VERSION 5.7 ;
  NAMESCASESENSITIVE ON ;
  NOWIREEXTENSIONATPIN ON ;
  DIVIDERCHAR "/" ;
  BUSBITCHARS "[]" ;
UNITS
  DATABASE MICRONS 200 ;
END UNITS

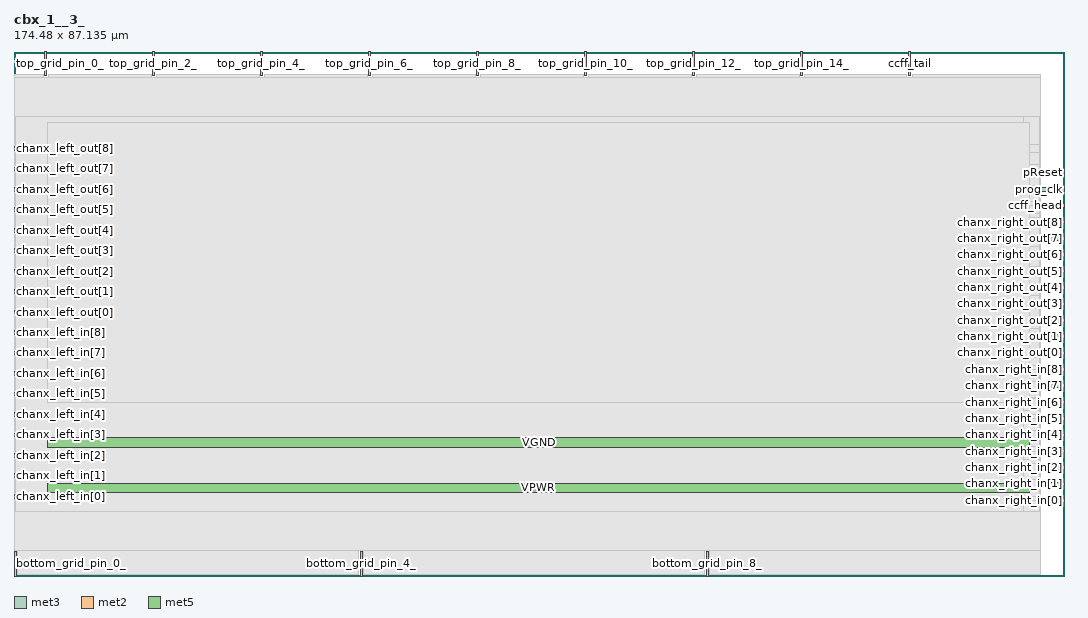
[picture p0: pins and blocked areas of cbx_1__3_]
MACRO cbx_1__3_
  CLASS BLOCK ;
  FOREIGN cbx_1__3_ ;
  ORIGIN 0.000 0.000 ;
  SIZE 174.480 BY 87.135 ;
  PIN chanx_left_in[0]
    DIRECTION INPUT ;
    PORT
      LAYER met3 ;
        RECT 0.000 12.960 4.000 13.560 ;
    END
  END chanx_left_in[0]
  PIN chanx_left_in[1]
    DIRECTION INPUT ;
    PORT
      LAYER met3 ;
        RECT 0.000 16.360 4.000 16.960 ;
    END
  END chanx_left_in[1]
  PIN chanx_left_in[2]
    DIRECTION INPUT ;
    PORT
      LAYER met3 ;
        RECT 0.000 19.760 4.000 20.360 ;
    END
  END chanx_left_in[2]
  PIN chanx_left_in[3]
    DIRECTION INPUT ;
    PORT
      LAYER met3 ;
        RECT 0.000 23.160 4.000 23.760 ;
    END
  END chanx_left_in[3]
  PIN chanx_left_in[4]
    DIRECTION INPUT ;
    PORT
      LAYER met3 ;
        RECT 0.000 26.560 4.000 27.160 ;
    END
  END chanx_left_in[4]
  PIN chanx_left_in[5]
    DIRECTION INPUT ;
    PORT
      LAYER met3 ;
        RECT 0.000 29.960 4.000 30.560 ;
    END
  END chanx_left_in[5]
  PIN chanx_left_in[6]
    DIRECTION INPUT ;
    PORT
      LAYER met3 ;
        RECT 0.000 33.360 4.000 33.960 ;
    END
  END chanx_left_in[6]
  PIN chanx_left_in[7]
    DIRECTION INPUT ;
    PORT
      LAYER met3 ;
        RECT 0.000 36.760 4.000 37.360 ;
    END
  END chanx_left_in[7]
  PIN chanx_left_in[8]
    DIRECTION INPUT ;
    PORT
      LAYER met3 ;
        RECT 0.000 40.160 4.000 40.760 ;
    END
  END chanx_left_in[8]
  PIN chanx_left_out[0]
    DIRECTION OUTPUT TRISTATE ;
    PORT
      LAYER met3 ;
        RECT 0.000 43.560 4.000 44.160 ;
    END
  END chanx_left_out[0]
  PIN chanx_left_out[1]
    DIRECTION OUTPUT TRISTATE ;
    PORT
      LAYER met3 ;
        RECT 0.000 46.960 4.000 47.560 ;
    END
  END chanx_left_out[1]
  PIN chanx_left_out[2]
    DIRECTION OUTPUT TRISTATE ;
    PORT
      LAYER met3 ;
        RECT 0.000 50.360 4.000 50.960 ;
    END
  END chanx_left_out[2]
  PIN chanx_left_out[3]
    DIRECTION OUTPUT TRISTATE ;
    PORT
      LAYER met3 ;
        RECT 0.000 53.760 4.000 54.360 ;
    END
  END chanx_left_out[3]
  PIN chanx_left_out[4]
    DIRECTION OUTPUT TRISTATE ;
    PORT
      LAYER met3 ;
        RECT 0.000 57.160 4.000 57.760 ;
    END
  END chanx_left_out[4]
  PIN chanx_left_out[5]
    DIRECTION OUTPUT TRISTATE ;
    PORT
      LAYER met3 ;
        RECT 0.000 60.560 4.000 61.160 ;
    END
  END chanx_left_out[5]
  PIN chanx_left_out[6]
    DIRECTION OUTPUT TRISTATE ;
    PORT
      LAYER met3 ;
        RECT 0.000 63.960 4.000 64.560 ;
    END
  END chanx_left_out[6]
  PIN chanx_left_out[7]
    DIRECTION OUTPUT TRISTATE ;
    PORT
      LAYER met3 ;
        RECT 0.000 67.360 4.000 67.960 ;
    END
  END chanx_left_out[7]
  PIN chanx_left_out[8]
    DIRECTION OUTPUT TRISTATE ;
    PORT
      LAYER met3 ;
        RECT 0.000 70.760 4.000 71.360 ;
    END
  END chanx_left_out[8]
  PIN top_grid_pin_0_
    DIRECTION OUTPUT TRISTATE ;
    PORT
      LAYER met2 ;
        RECT 5.150 83.135 5.430 87.135 ;
    END
  END top_grid_pin_0_
  PIN top_grid_pin_2_
    DIRECTION OUTPUT TRISTATE ;
    PORT
      LAYER met2 ;
        RECT 23.090 83.135 23.370 87.135 ;
    END
  END top_grid_pin_2_
  PIN top_grid_pin_4_
    DIRECTION OUTPUT TRISTATE ;
    PORT
      LAYER met2 ;
        RECT 41.030 83.135 41.310 87.135 ;
    END
  END top_grid_pin_4_
  PIN top_grid_pin_6_
    DIRECTION OUTPUT TRISTATE ;
    PORT
      LAYER met2 ;
        RECT 58.970 83.135 59.250 87.135 ;
    END
  END top_grid_pin_6_
  PIN top_grid_pin_8_
    DIRECTION OUTPUT TRISTATE ;
    PORT
      LAYER met2 ;
        RECT 76.910 83.135 77.190 87.135 ;
    END
  END top_grid_pin_8_
  PIN top_grid_pin_10_
    DIRECTION OUTPUT TRISTATE ;
    PORT
      LAYER met2 ;
        RECT 94.850 83.135 95.130 87.135 ;
    END
  END top_grid_pin_10_
  PIN top_grid_pin_12_
    DIRECTION OUTPUT TRISTATE ;
    PORT
      LAYER met2 ;
        RECT 112.790 83.135 113.070 87.135 ;
    END
  END top_grid_pin_12_
  PIN top_grid_pin_14_
    DIRECTION OUTPUT TRISTATE ;
    PORT
      LAYER met2 ;
        RECT 130.730 83.135 131.010 87.135 ;
    END
  END top_grid_pin_14_
  PIN ccff_tail
    DIRECTION OUTPUT TRISTATE ;
    PORT
      LAYER met2 ;
        RECT 148.670 83.135 148.950 87.135 ;
    END
  END ccff_tail
  PIN chanx_right_in[0]
    DIRECTION INPUT ;
    PORT
      LAYER met3 ;
        RECT 170.480 12.280 174.480 12.880 ;
    END
  END chanx_right_in[0]
  PIN chanx_right_in[1]
    DIRECTION INPUT ;
    PORT
      LAYER met3 ;
        RECT 170.480 15.000 174.480 15.600 ;
    END
  END chanx_right_in[1]
  PIN chanx_right_in[2]
    DIRECTION INPUT ;
    PORT
      LAYER met3 ;
        RECT 170.480 17.720 174.480 18.320 ;
    END
  END chanx_right_in[2]
  PIN chanx_right_in[3]
    DIRECTION INPUT ;
    PORT
      LAYER met3 ;
        RECT 170.480 20.440 174.480 21.040 ;
    END
  END chanx_right_in[3]
  PIN chanx_right_in[4]
    DIRECTION INPUT ;
    PORT
      LAYER met3 ;
        RECT 170.480 23.160 174.480 23.760 ;
    END
  END chanx_right_in[4]
  PIN chanx_right_in[5]
    DIRECTION INPUT ;
    PORT
      LAYER met3 ;
        RECT 170.480 25.880 174.480 26.480 ;
    END
  END chanx_right_in[5]
  PIN chanx_right_in[6]
    DIRECTION INPUT ;
    PORT
      LAYER met3 ;
        RECT 170.480 28.600 174.480 29.200 ;
    END
  END chanx_right_in[6]
  PIN chanx_right_in[7]
    DIRECTION INPUT ;
    PORT
      LAYER met3 ;
        RECT 170.480 31.320 174.480 31.920 ;
    END
  END chanx_right_in[7]
  PIN chanx_right_in[8]
    DIRECTION INPUT ;
    PORT
      LAYER met3 ;
        RECT 170.480 34.040 174.480 34.640 ;
    END
  END chanx_right_in[8]
  PIN chanx_right_out[0]
    DIRECTION OUTPUT TRISTATE ;
    PORT
      LAYER met3 ;
        RECT 170.480 36.760 174.480 37.360 ;
    END
  END chanx_right_out[0]
  PIN chanx_right_out[1]
    DIRECTION OUTPUT TRISTATE ;
    PORT
      LAYER met3 ;
        RECT 170.480 39.480 174.480 40.080 ;
    END
  END chanx_right_out[1]
  PIN chanx_right_out[2]
    DIRECTION OUTPUT TRISTATE ;
    PORT
      LAYER met3 ;
        RECT 170.480 42.200 174.480 42.800 ;
    END
  END chanx_right_out[2]
  PIN chanx_right_out[3]
    DIRECTION OUTPUT TRISTATE ;
    PORT
      LAYER met3 ;
        RECT 170.480 44.920 174.480 45.520 ;
    END
  END chanx_right_out[3]
  PIN chanx_right_out[4]
    DIRECTION OUTPUT TRISTATE ;
    PORT
      LAYER met3 ;
        RECT 170.480 47.640 174.480 48.240 ;
    END
  END chanx_right_out[4]
  PIN chanx_right_out[5]
    DIRECTION OUTPUT TRISTATE ;
    PORT
      LAYER met3 ;
        RECT 170.480 50.360 174.480 50.960 ;
    END
  END chanx_right_out[5]
  PIN chanx_right_out[6]
    DIRECTION OUTPUT TRISTATE ;
    PORT
      LAYER met3 ;
        RECT 170.480 53.080 174.480 53.680 ;
    END
  END chanx_right_out[6]
  PIN chanx_right_out[7]
    DIRECTION OUTPUT TRISTATE ;
    PORT
      LAYER met3 ;
        RECT 170.480 55.800 174.480 56.400 ;
    END
  END chanx_right_out[7]
  PIN chanx_right_out[8]
    DIRECTION OUTPUT TRISTATE ;
    PORT
      LAYER met3 ;
        RECT 170.480 58.520 174.480 59.120 ;
    END
  END chanx_right_out[8]
  PIN ccff_head
    DIRECTION INPUT ;
    PORT
      LAYER met3 ;
        RECT 170.480 61.240 174.480 61.840 ;
    END
  END ccff_head
  PIN prog_clk
    DIRECTION INPUT ;
    PORT
      LAYER met3 ;
        RECT 170.480 63.960 174.480 64.560 ;
    END
  END prog_clk
  PIN pReset
    DIRECTION INPUT ;
    PORT
      LAYER met3 ;
        RECT 170.480 66.680 174.480 67.280 ;
    END
  END pReset
  PIN bottom_grid_pin_0_
    DIRECTION OUTPUT TRISTATE ;
    PORT
      LAYER met2 ;
        RECT 0.090 0.000 0.370 4.000 ;
    END
  END bottom_grid_pin_0_
  PIN bottom_grid_pin_4_
    DIRECTION OUTPUT TRISTATE ;
    PORT
      LAYER met2 ;
        RECT 57.590 0.000 57.870 4.000 ;
    END
  END bottom_grid_pin_4_
  PIN bottom_grid_pin_8_
    DIRECTION OUTPUT TRISTATE ;
    PORT
      LAYER met2 ;
        RECT 115.090 0.000 115.370 4.000 ;
    END
  END bottom_grid_pin_8_
  PIN VPWR
    DIRECTION INPUT ;
    USE POWER ;
    PORT
      LAYER met5 ;
        RECT 5.520 13.840 168.820 15.440 ;
    END
  END VPWR
  PIN VGND
    DIRECTION INPUT ;
    USE GROUND ;
    PORT
      LAYER met5 ;
        RECT 5.520 21.340 168.820 22.940 ;
    END
  END VGND
  OBS
      LAYER li1 ;
        RECT 5.520 10.795 168.820 76.245 ;
      LAYER met1 ;
        RECT 0.070 10.640 170.590 76.400 ;
      LAYER met2 ;
        RECT 0.090 82.855 4.870 83.370 ;
        RECT 5.710 82.855 22.810 83.370 ;
        RECT 23.650 82.855 40.750 83.370 ;
        RECT 41.590 82.855 58.690 83.370 ;
        RECT 59.530 82.855 76.630 83.370 ;
        RECT 77.470 82.855 94.570 83.370 ;
        RECT 95.410 82.855 112.510 83.370 ;
        RECT 113.350 82.855 130.450 83.370 ;
        RECT 131.290 82.855 148.390 83.370 ;
        RECT 149.230 82.855 170.570 83.370 ;
        RECT 0.090 4.280 170.570 82.855 ;
        RECT 0.650 0.270 57.310 4.280 ;
        RECT 58.150 0.270 114.810 4.280 ;
        RECT 115.650 0.270 170.570 4.280 ;
      LAYER met3 ;
        RECT 0.270 71.760 170.480 76.325 ;
        RECT 4.400 70.360 170.480 71.760 ;
        RECT 0.270 68.360 170.480 70.360 ;
        RECT 4.400 67.680 170.480 68.360 ;
        RECT 4.400 66.960 170.080 67.680 ;
        RECT 0.270 66.280 170.080 66.960 ;
        RECT 0.270 64.960 170.480 66.280 ;
        RECT 4.400 63.560 170.080 64.960 ;
        RECT 0.270 62.240 170.480 63.560 ;
        RECT 0.270 61.560 170.080 62.240 ;
        RECT 4.400 60.840 170.080 61.560 ;
        RECT 4.400 60.160 170.480 60.840 ;
        RECT 0.270 59.520 170.480 60.160 ;
        RECT 0.270 58.160 170.080 59.520 ;
        RECT 4.400 58.120 170.080 58.160 ;
        RECT 4.400 56.800 170.480 58.120 ;
        RECT 4.400 56.760 170.080 56.800 ;
        RECT 0.270 55.400 170.080 56.760 ;
        RECT 0.270 54.760 170.480 55.400 ;
        RECT 4.400 54.080 170.480 54.760 ;
        RECT 4.400 53.360 170.080 54.080 ;
        RECT 0.270 52.680 170.080 53.360 ;
        RECT 0.270 51.360 170.480 52.680 ;
        RECT 4.400 49.960 170.080 51.360 ;
        RECT 0.270 48.640 170.480 49.960 ;
        RECT 0.270 47.960 170.080 48.640 ;
        RECT 4.400 47.240 170.080 47.960 ;
        RECT 4.400 46.560 170.480 47.240 ;
        RECT 0.270 45.920 170.480 46.560 ;
        RECT 0.270 44.560 170.080 45.920 ;
        RECT 4.400 44.520 170.080 44.560 ;
        RECT 4.400 43.200 170.480 44.520 ;
        RECT 4.400 43.160 170.080 43.200 ;
        RECT 0.270 41.800 170.080 43.160 ;
        RECT 0.270 41.160 170.480 41.800 ;
        RECT 4.400 40.480 170.480 41.160 ;
        RECT 4.400 39.760 170.080 40.480 ;
        RECT 0.270 39.080 170.080 39.760 ;
        RECT 0.270 37.760 170.480 39.080 ;
        RECT 4.400 36.360 170.080 37.760 ;
        RECT 0.270 35.040 170.480 36.360 ;
        RECT 0.270 34.360 170.080 35.040 ;
        RECT 4.400 33.640 170.080 34.360 ;
        RECT 4.400 32.960 170.480 33.640 ;
        RECT 0.270 32.320 170.480 32.960 ;
        RECT 0.270 30.960 170.080 32.320 ;
        RECT 4.400 30.920 170.080 30.960 ;
        RECT 4.400 29.600 170.480 30.920 ;
        RECT 4.400 29.560 170.080 29.600 ;
        RECT 0.270 28.200 170.080 29.560 ;
        RECT 0.270 27.560 170.480 28.200 ;
        RECT 4.400 26.880 170.480 27.560 ;
        RECT 4.400 26.160 170.080 26.880 ;
        RECT 0.270 25.480 170.080 26.160 ;
        RECT 0.270 24.160 170.480 25.480 ;
        RECT 4.400 22.760 170.080 24.160 ;
        RECT 0.270 21.440 170.480 22.760 ;
        RECT 0.270 20.760 170.080 21.440 ;
        RECT 4.400 20.040 170.080 20.760 ;
        RECT 4.400 19.360 170.480 20.040 ;
        RECT 0.270 18.720 170.480 19.360 ;
        RECT 0.270 17.360 170.080 18.720 ;
        RECT 4.400 17.320 170.080 17.360 ;
        RECT 4.400 16.000 170.480 17.320 ;
        RECT 4.400 15.960 170.080 16.000 ;
        RECT 0.270 14.600 170.080 15.960 ;
        RECT 0.270 13.960 170.480 14.600 ;
        RECT 4.400 13.280 170.480 13.960 ;
        RECT 4.400 12.560 170.080 13.280 ;
        RECT 0.270 11.880 170.080 12.560 ;
        RECT 0.270 10.715 170.480 11.880 ;
      LAYER met4 ;
        RECT 0.295 10.640 167.820 76.400 ;
      LAYER met5 ;
        RECT 5.520 28.840 168.820 75.440 ;
  END
END cbx_1__3_
END LIBRARY

